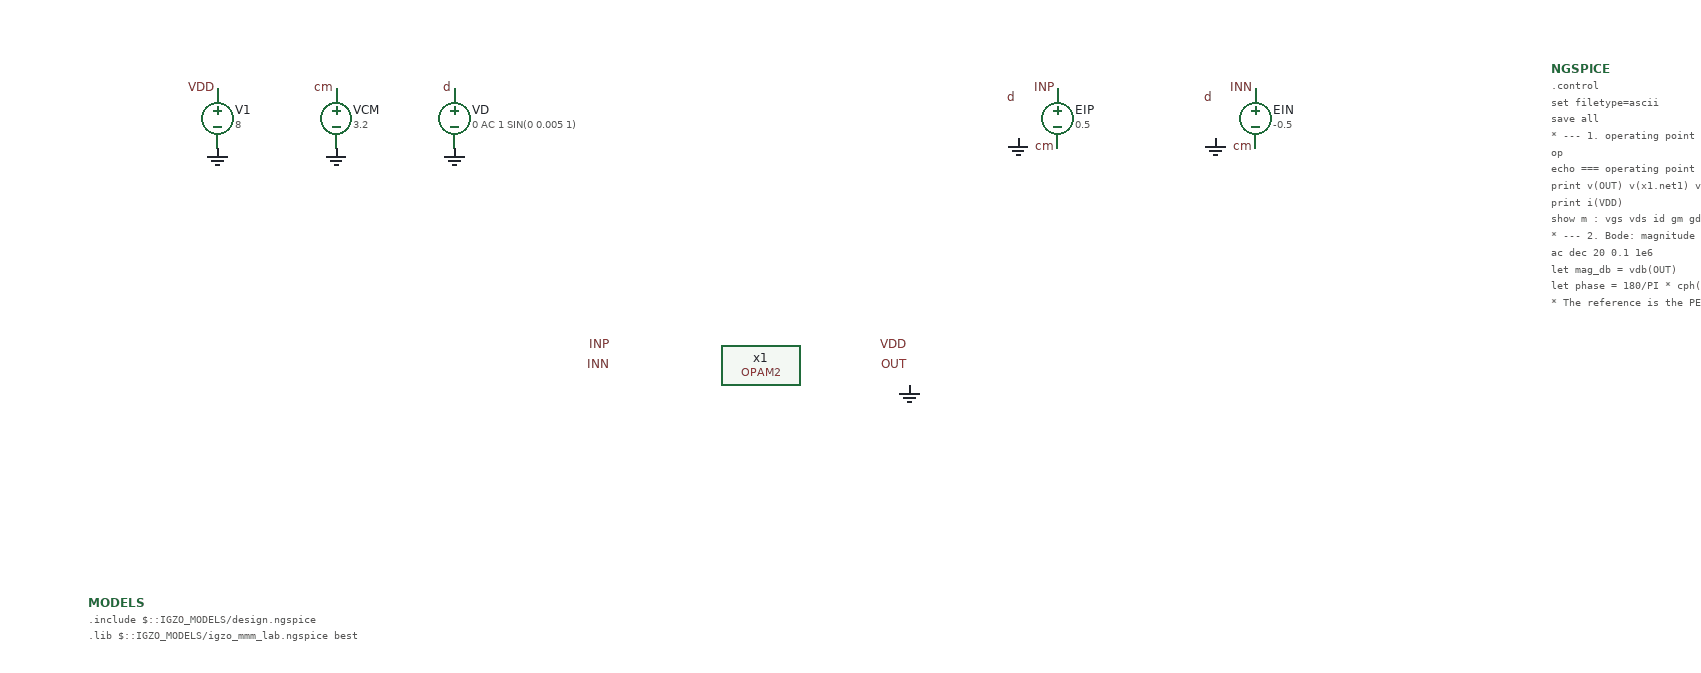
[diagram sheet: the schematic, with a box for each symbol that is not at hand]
v {xschem version=3.4.8RC file_version=1.3
* OPAM2 open-loop testbench - Zysset topology, all-enhancement IGZO
*
* Generated by sim/make_testbench.py - do not edit by hand, regenerate.
}
G {}
K {}
V {}
S {}
E {}
C {MMM-LAB DESIGN/OPAM/OPAM2.sym} 700 -400 0 0 {name=x1}
C {devices/lab_pin.sym} 850 -420 0 0 {name=VDD lab=VDD}
C {devices/lab_pin.sym} 550 -420 0 0 {name=INP lab=INP}
C {devices/lab_pin.sym} 850 -400 0 0 {name=OUT lab=OUT}
C {devices/lab_pin.sym} 550 -400 0 0 {name=INN lab=INN}
C {devices/gnd.sym} 850 -380 0 0 {name=gvss lab=0}
C {devices/vsource.sym} 150 -650 0 0 {name=V1 value="8" savecurrent=false}
C {devices/lab_pin.sym} 150 -680 0 0 {name=VDD lab=VDD}
C {devices/gnd.sym} 150 -620 0 0 {name=gV1 lab=0}
C {devices/vsource.sym} 270 -650 0 0 {name=VCM value="3.2" savecurrent=false}
C {devices/lab_pin.sym} 270 -680 0 0 {name=cm lab=cm}
C {devices/gnd.sym} 270 -620 0 0 {name=gVCM lab=0}
C {devices/vsource.sym} 390 -650 0 0 {name=VD value="0 AC 1 SIN(0 0.005 1)" savecurrent=false}
C {devices/lab_pin.sym} 390 -680 0 0 {name=d lab=d}
C {devices/gnd.sym} 390 -620 0 0 {name=gVD lab=0}
C {devices/vcvs.sym} 1000 -650 0 0 {name=EIP value=0.5}
C {devices/lab_pin.sym} 1000 -680 0 0 {name=INP lab=INP}
C {devices/lab_pin.sym} 1000 -620 0 0 {name=cm lab=cm}
C {devices/lab_pin.sym} 960 -670 0 0 {name=d lab=d}
C {devices/gnd.sym} 960 -630 0 0 {name=gEIP lab=0}
C {devices/vcvs.sym} 1200 -650 0 0 {name=EIN value=-0.5}
C {devices/lab_pin.sym} 1200 -680 0 0 {name=INN lab=INN}
C {devices/lab_pin.sym} 1200 -620 0 0 {name=cm lab=cm}
C {devices/lab_pin.sym} 1160 -670 0 0 {name=d lab=d}
C {devices/gnd.sym} 1160 -630 0 0 {name=gEIN lab=0}
C {devices/code_shown.sym} 20 -160 0 0 {name=MODELS only_toplevel=true
format="tcleval( @value )"
value="
.include $::IGZO_MODELS/design.ngspice
.lib $::IGZO_MODELS/igzo_mmm_lab.ngspice best
"}
C {devices/code_shown.sym} 1500 -700 0 0 {name=NGSPICE only_toplevel=true
value="
.control
set filetype=ascii
save all

* --- 1. operating point ----------------------------------------------------
op
echo === operating point ===
print v(OUT) v(x1.net1) v(x1.net2) v(x1.net3) v(x1.net4) v(x1.net5) v(x1.net6)
print i(VDD)
show m : vgs vds id gm gds

* --- 2. Bode: magnitude and phase ------------------------------------------
ac dec 20 0.1 1e6
let mag_db = vdb(OUT)
let phase  = 180/PI * cph(v(OUT))
* The reference is the PEAK of the response, not the value at 0.1 Hz.  OPAM
* rises about 2 dB from 0.1 Hz to a peak near 2 Hz, so reading the gain at the
* bottom of the sweep understates it and puts f-3dB in the wrong place.
meas ac av_dc  FIND vdb(OUT) AT=0.1
meas ac av_max MAX vdb(OUT)
meas ac f3db   WHEN vdb(OUT)='av_max-3' FALL=1
meas ac funity WHEN vdb(OUT)=0 FALL=1
* Phase margin against the DC phase, not against zero: an inverting amplifier
* already sits at 180 degrees at DC, and subtracting it is what makes the
* number mean the same thing for both circuits.
meas ac ph_dc FIND phase AT=0.1
meas ac ph_u  FIND phase WHEN vdb(OUT)=0 FALL=1
let pm = 180 + (ph_u - ph_dc)
echo === bode: gain, corner, unity gain, phase margin ===
print av_dc av_max f3db funity ph_dc ph_u pm
* the AC vectors die with the plot, so keep what the later runs need
set avmaxs = $&av_max
set f3s    = $&f3db
plot mag_db
plot phase

* --- 3. input / output relation --------------------------------------------
dc V4 -2 2 0.01
echo === transfer: output against differential input ===
meas dc out_max MAX v(OUT)
meas dc out_min MIN v(OUT)
meas dc vo_0    FIND v(OUT) AT=0
meas dc vo_p    FIND v(OUT) AT=0.01
meas dc vo_m    FIND v(OUT) AT=-0.01
let slope    = (vo_p - vo_m) / 0.02
let slope_db = db(abs(slope))
print out_max out_min vo_0 slope slope_db
plot v(OUT)

* --- 4. sine inside the band -----------------------------------------------
* a decade below the corner, and small enough that the output cannot clip
let fsig = $f3s / 10
let amp  = 0.3 / (10^($avmaxs/20))
set fsigs = $&fsig
set amps  = $&amp
echo === sine: frequency and amplitude derived from the AC run ===
print fsig amp
* the honest reference for the cross-check is the AC gain at THIS frequency,
* not the flat-band figure - one extra single-point AC run buys that
ac lin 1 $fsigs $fsigs
let av_ref = vdb(OUT)
set avrefs = $&av_ref
alter V4 sin = [ 0 $amps $fsigs ]
* Settle for 200 cycles before measuring, and step at 50 points per cycle.
* This is not caution for its own sake: OPAM's bootstrap gate node is held
* only by the off-device leakage (r_off in opam_core.spice), so the signal
* pumps charge into it through C2 and the node drifts for tens of seconds
* before it finds equilibrium.  Measured over 12 cycles the gain reads several
* dB high and is still moving; by 150 cycles it has converged and stays put
* through 1000.  OPAM2 has no such node and settles at once, so the same
* window costs it only simulation time.
let tskip = 200 / $fsigs
let tstop = tskip + 6 / $fsigs
set ts = $&tstop
set tk = $&tskip
let tstep = 1 / (50 * $fsigs)
set tstp = $&tstep
tran $tstp $ts $tk
echo === sine: measured input and output ===
meas tran vi_pp PP v(INN,INP)   FROM=$tk TO=$ts
meas tran vo_pp PP v(OUT) FROM=$tk TO=$ts
let av_tran = db(vo_pp / vi_pp)
print vi_pp vo_pp av_tran
plot v(OUT) v(INN,INP)

* --- 5. the two gains have to agree ----------------------------------------
* A gap here is a result, not a glitch.  The AC run linearises about the DC
* operating point; the transient is the circuit actually running.  If they
* disagree by more than about 1 dB, either the sine is clipping or the
* operating point moves once the signal is applied - and for a floating
* bootstrap node, it does.
let gain_err = av_tran - $avrefs
print gain_err
echo === done ===
.endc
"}
C {devices/title.sym} 160 -30 0 0 {name=l5 author="UCI/INRF - MMM Lab"}
